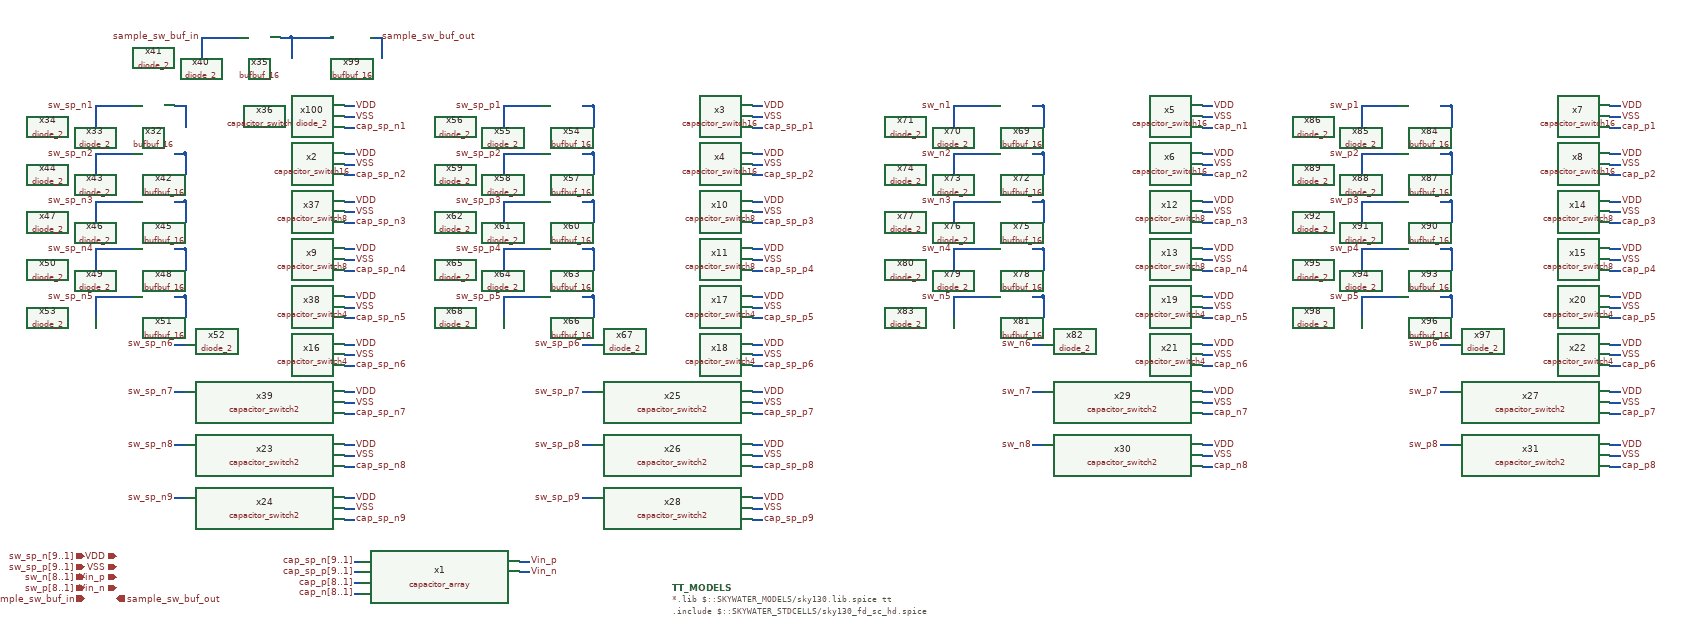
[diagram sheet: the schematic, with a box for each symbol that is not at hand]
v {xschem version=3.1.0 file_version=1.2
}
G {}
K {}
V {}
S {}
E {}
N 690 -110 700 -110 {
lab=cap_sp_n[9..1]}
N 690 -90 700 -90 {
lab=cap_sp_p[9..1]}
N 690 -70 700 -70 {
lab=cap_p[8..1]}
N 690 -50 700 -50 {
lab=cap_n[8..1]}
N 1000 -110 1020 -110 {
lab=Vin_p}
N 1000 -90 1020 -90 {
lab=Vin_n}
N 670 -930 690 -930 {
lab=cap_sp_n1}
N 670 -970 690 -970 {
lab=VDD}
N 670 -950 690 -950 {
lab=VSS}
N 350 -970 370 -970 {
lab=sw_sp_n1}
N 670 -840 690 -840 {
lab=cap_sp_n2}
N 670 -880 690 -880 {
lab=VDD}
N 670 -860 690 -860 {
lab=VSS}
N 350 -880 370 -880 {
lab=sw_sp_n2}
N 670 -750 690 -750 {
lab=cap_sp_n3}
N 670 -790 690 -790 {
lab=VDD}
N 670 -770 690 -770 {
lab=VSS}
N 350 -790 370 -790 {
lab=sw_sp_n3}
N 670 -660 690 -660 {
lab=cap_sp_n4}
N 670 -700 690 -700 {
lab=VDD}
N 670 -680 690 -680 {
lab=VSS}
N 350 -700 370 -700 {
lab=sw_sp_n4}
N 670 -570 690 -570 {
lab=cap_sp_n5}
N 670 -610 690 -610 {
lab=VDD}
N 670 -590 690 -590 {
lab=VSS}
N 350 -610 370 -610 {
lab=sw_sp_n5}
N 670 -480 690 -480 {
lab=cap_sp_n6}
N 670 -520 690 -520 {
lab=VDD}
N 670 -500 690 -500 {
lab=VSS}
N 350 -520 370 -520 {
lab=sw_sp_n6}
N 670 -390 690 -390 {
lab=cap_sp_n7}
N 670 -430 690 -430 {
lab=VDD}
N 670 -410 690 -410 {
lab=VSS}
N 350 -430 370 -430 {
lab=sw_sp_n7}
N 670 -290 690 -290 {
lab=cap_sp_n8}
N 670 -330 690 -330 {
lab=VDD}
N 670 -310 690 -310 {
lab=VSS}
N 350 -330 370 -330 {
lab=sw_sp_n8}
N 670 -190 690 -190 {
lab=cap_sp_n9}
N 670 -230 690 -230 {
lab=VDD}
N 670 -210 690 -210 {
lab=VSS}
N 350 -230 370 -230 {
lab=sw_sp_n9}
N 1440 -930 1460 -930 {
lab=cap_sp_p1}
N 1440 -970 1460 -970 {
lab=VDD}
N 1440 -950 1460 -950 {
lab=VSS}
N 1120 -970 1140 -970 {
lab=sw_sp_p1}
N 1440 -840 1460 -840 {
lab=cap_sp_p2}
N 1440 -880 1460 -880 {
lab=VDD}
N 1440 -860 1460 -860 {
lab=VSS}
N 1120 -880 1140 -880 {
lab=sw_sp_p2}
N 1440 -750 1460 -750 {
lab=cap_sp_p3}
N 1440 -790 1460 -790 {
lab=VDD}
N 1440 -770 1460 -770 {
lab=VSS}
N 1120 -790 1140 -790 {
lab=sw_sp_p3}
N 1440 -660 1460 -660 {
lab=cap_sp_p4}
N 1440 -700 1460 -700 {
lab=VDD}
N 1440 -680 1460 -680 {
lab=VSS}
N 1120 -700 1140 -700 {
lab=sw_sp_p4}
N 1440 -570 1460 -570 {
lab=cap_sp_p5}
N 1440 -610 1460 -610 {
lab=VDD}
N 1440 -590 1460 -590 {
lab=VSS}
N 1120 -610 1140 -610 {
lab=sw_sp_p5}
N 1440 -480 1460 -480 {
lab=cap_sp_p6}
N 1440 -520 1460 -520 {
lab=VDD}
N 1440 -500 1460 -500 {
lab=VSS}
N 1120 -520 1140 -520 {
lab=sw_sp_p6}
N 1440 -390 1460 -390 {
lab=cap_sp_p7}
N 1440 -430 1460 -430 {
lab=VDD}
N 1440 -410 1460 -410 {
lab=VSS}
N 1120 -430 1140 -430 {
lab=sw_sp_p7}
N 1440 -290 1460 -290 {
lab=cap_sp_p8}
N 1440 -330 1460 -330 {
lab=VDD}
N 1440 -310 1460 -310 {
lab=VSS}
N 1120 -330 1140 -330 {
lab=sw_sp_p8}
N 1440 -190 1460 -190 {
lab=cap_sp_p9}
N 1440 -230 1460 -230 {
lab=VDD}
N 1440 -210 1460 -210 {
lab=VSS}
N 1120 -230 1140 -230 {
lab=sw_sp_p9}
N 3060 -930 3080 -930 {
lab=cap_p1}
N 3060 -970 3080 -970 {
lab=VDD}
N 3060 -950 3080 -950 {
lab=VSS}
N 2740 -970 2760 -970 {
lab=sw_p1}
N 3060 -840 3080 -840 {
lab=cap_p2}
N 3060 -880 3080 -880 {
lab=VDD}
N 3060 -860 3080 -860 {
lab=VSS}
N 2740 -880 2760 -880 {
lab=sw_p2}
N 3060 -750 3080 -750 {
lab=cap_p3}
N 3060 -790 3080 -790 {
lab=VDD}
N 3060 -770 3080 -770 {
lab=VSS}
N 2740 -790 2760 -790 {
lab=sw_p3}
N 3060 -660 3080 -660 {
lab=cap_p4}
N 3060 -700 3080 -700 {
lab=VDD}
N 3060 -680 3080 -680 {
lab=VSS}
N 2740 -700 2760 -700 {
lab=sw_p4}
N 3060 -570 3080 -570 {
lab=cap_p5}
N 3060 -610 3080 -610 {
lab=VDD}
N 3060 -590 3080 -590 {
lab=VSS}
N 2740 -610 2760 -610 {
lab=sw_p5}
N 3060 -480 3080 -480 {
lab=cap_p6}
N 3060 -520 3080 -520 {
lab=VDD}
N 3060 -500 3080 -500 {
lab=VSS}
N 2740 -520 2760 -520 {
lab=sw_p6}
N 3060 -390 3080 -390 {
lab=cap_p7}
N 3060 -430 3080 -430 {
lab=VDD}
N 3060 -410 3080 -410 {
lab=VSS}
N 2740 -430 2760 -430 {
lab=sw_p7}
N 3060 -290 3080 -290 {
lab=cap_p8}
N 3060 -330 3080 -330 {
lab=VDD}
N 3060 -310 3080 -310 {
lab=VSS}
N 2740 -330 2760 -330 {
lab=sw_p8}
N 2290 -930 2310 -930 {
lab=cap_n1}
N 2290 -970 2310 -970 {
lab=VDD}
N 2290 -950 2310 -950 {
lab=VSS}
N 1970 -970 1990 -970 {
lab=sw_n1}
N 2290 -840 2310 -840 {
lab=cap_n2}
N 2290 -880 2310 -880 {
lab=VDD}
N 2290 -860 2310 -860 {
lab=VSS}
N 1970 -880 1990 -880 {
lab=sw_n2}
N 2290 -750 2310 -750 {
lab=cap_n3}
N 2290 -790 2310 -790 {
lab=VDD}
N 2290 -770 2310 -770 {
lab=VSS}
N 1970 -790 1990 -790 {
lab=sw_n3}
N 2290 -660 2310 -660 {
lab=cap_n4}
N 2290 -700 2310 -700 {
lab=VDD}
N 2290 -680 2310 -680 {
lab=VSS}
N 1970 -700 1990 -700 {
lab=sw_n4}
N 2290 -570 2310 -570 {
lab=cap_n5}
N 2290 -610 2310 -610 {
lab=VDD}
N 2290 -590 2310 -590 {
lab=VSS}
N 1970 -610 1990 -610 {
lab=sw_n5}
N 2290 -480 2310 -480 {
lab=cap_n6}
N 2290 -520 2310 -520 {
lab=VDD}
N 2290 -500 2310 -500 {
lab=VSS}
N 1970 -520 1990 -520 {
lab=sw_n6}
N 2290 -390 2310 -390 {
lab=cap_n7}
N 2290 -430 2310 -430 {
lab=VDD}
N 2290 -410 2310 -410 {
lab=VSS}
N 1970 -430 1990 -430 {
lab=sw_n7}
N 2290 -290 2310 -290 {
lab=cap_n8}
N 2290 -330 2310 -330 {
lab=VDD}
N 2290 -310 2310 -310 {
lab=VSS}
N 1970 -330 1990 -330 {
lab=sw_n8}
N 370 -970 370 -930 {}
N 210 -970 270 -970 {}
N 200 -970 200 -930 {}
N 200 -970 210 -970 {}
N 550 -1100 570 -1100 {
lab=sw_sp_n1}
N 570 -1100 570 -1060 {}
N 410 -1100 470 -1100 {}
N 400 -1100 400 -1060 {}
N 400 -1100 410 -1100 {}
N 350 -880 370 -880 {
lab=sw_sp_n1}
N 370 -880 370 -840 {}
N 210 -880 270 -880 {}
N 200 -880 200 -840 {}
N 200 -880 210 -880 {}
N 350 -790 370 -790 {
lab=sw_sp_n1}
N 370 -790 370 -750 {}
N 210 -790 270 -790 {}
N 200 -790 200 -750 {}
N 200 -790 210 -790 {}
N 350 -700 370 -700 {
lab=sw_sp_n1}
N 370 -700 370 -660 {}
N 210 -700 270 -700 {}
N 200 -700 200 -660 {}
N 200 -700 210 -700 {}
N 350 -610 370 -610 {
lab=sw_sp_n1}
N 370 -610 370 -570 {}
N 210 -610 270 -610 {}
N 200 -610 200 -570 {}
N 200 -610 210 -610 {}
N 1120 -970 1140 -970 {
lab=sw_sp_n1}
N 1140 -970 1140 -930 {}
N 980 -970 1040 -970 {}
N 970 -970 970 -930 {}
N 970 -970 980 -970 {}
N 1120 -880 1140 -880 {
lab=sw_sp_n1}
N 1140 -880 1140 -840 {}
N 980 -880 1040 -880 {}
N 970 -880 970 -840 {}
N 970 -880 980 -880 {}
N 1120 -790 1140 -790 {
lab=sw_sp_n1}
N 1140 -790 1140 -750 {}
N 980 -790 1040 -790 {}
N 970 -790 970 -750 {}
N 970 -790 980 -790 {}
N 1120 -700 1140 -700 {
lab=sw_sp_n1}
N 1140 -700 1140 -660 {}
N 980 -700 1040 -700 {}
N 970 -700 970 -660 {}
N 970 -700 980 -700 {}
N 1120 -610 1140 -610 {
lab=sw_sp_n1}
N 1140 -610 1140 -570 {}
N 980 -610 1040 -610 {}
N 970 -610 970 -570 {}
N 970 -610 980 -610 {}
N 1970 -970 1990 -970 {
lab=sw_sp_n1}
N 1990 -970 1990 -930 {}
N 1830 -970 1890 -970 {}
N 1820 -970 1820 -930 {}
N 1820 -970 1830 -970 {}
N 1970 -880 1990 -880 {
lab=sw_sp_n1}
N 1990 -880 1990 -840 {}
N 1830 -880 1890 -880 {}
N 1820 -880 1820 -840 {}
N 1820 -880 1830 -880 {}
N 1970 -790 1990 -790 {
lab=sw_sp_n1}
N 1990 -790 1990 -750 {}
N 1830 -790 1890 -790 {}
N 1820 -790 1820 -750 {}
N 1820 -790 1830 -790 {}
N 1970 -700 1990 -700 {
lab=sw_sp_n1}
N 1990 -700 1990 -660 {}
N 1830 -700 1890 -700 {}
N 1820 -700 1820 -660 {}
N 1820 -700 1830 -700 {}
N 1970 -610 1990 -610 {
lab=sw_sp_n1}
N 1990 -610 1990 -570 {}
N 1830 -610 1890 -610 {}
N 1820 -610 1820 -570 {}
N 1820 -610 1830 -610 {}
N 2740 -970 2760 -970 {
lab=sw_sp_n1}
N 2760 -970 2760 -930 {}
N 2600 -970 2660 -970 {}
N 2590 -970 2590 -930 {}
N 2590 -970 2600 -970 {}
N 2740 -880 2760 -880 {
lab=sw_sp_n1}
N 2760 -880 2760 -840 {}
N 2600 -880 2660 -880 {}
N 2590 -880 2590 -840 {}
N 2590 -880 2600 -880 {}
N 2740 -790 2760 -790 {
lab=sw_sp_n1}
N 2760 -790 2760 -750 {}
N 2600 -790 2660 -790 {}
N 2590 -790 2590 -750 {}
N 2590 -790 2600 -790 {}
N 2740 -700 2760 -700 {
lab=sw_sp_n1}
N 2760 -700 2760 -660 {}
N 2600 -700 2660 -700 {}
N 2590 -700 2590 -660 {}
N 2590 -700 2600 -700 {}
N 2740 -610 2760 -610 {
lab=sw_sp_n1}
N 2760 -610 2760 -570 {}
N 2600 -610 2660 -610 {}
N 2590 -610 2590 -570 {}
N 2590 -610 2600 -610 {}
N 720 -1100 740 -1100 {
lab=sw_sp_n1}
N 740 -1100 740 -1060 {}
N 580 -1100 640 -1100 {}
N 570 -1100 580 -1100 {}
N 640 -1100 650 -1100 {}
C {devices/title.sym} 160 30 0 0 {name=l1 author="Dr. Aubrey Beal, Dr. Phillip Bailey, Micah Tseng"
}
C {src/capacitor_array/capacitor_array.sym} 850 -80 0 0 {name=x1 unit_cap_w=5 unit_cap_l=5
}
C {devices/iopin.sym} 240 -120 0 0 {name=p1 lab=VDD
}
C {devices/ipin.sym} 180 -120 0 0 {name=p3 lab=sw_sp_n[9..1]
}
C {devices/iopin.sym} 240 -100 0 0 {name=p4 lab=VSS
}
C {devices/iopin.sym} 240 -80 0 0 {name=p5 lab=Vin_p
}
C {devices/iopin.sym} 240 -60 0 0 {name=p6 lab=Vin_n
}
C {devices/ipin.sym} 180 -100 0 0 {name=p2 lab=sw_sp_p[9..1]
}
C {devices/ipin.sym} 180 -80 0 0 {name=p7 lab=sw_n[8..1]
}
C {devices/ipin.sym} 180 -60 0 0 {name=p8 lab=sw_p[8..1]
}
C {devices/lab_pin.sym} 690 -110 0 0 {name=l2 sig_type=std_logic lab=cap_sp_n[9..1]
}
C {devices/lab_pin.sym} 690 -90 0 0 {name=l3 sig_type=std_logic lab=cap_sp_p[9..1]
}
C {devices/lab_pin.sym} 690 -70 0 0 {name=l4 sig_type=std_logic lab=cap_p[8..1]
}
C {devices/lab_pin.sym} 690 -50 0 0 {name=l5 sig_type=std_logic lab=cap_n[8..1]
}
C {devices/lab_pin.sym} 1020 -110 2 0 {name=l6 sig_type=std_logic lab=Vin_p
}
C {devices/lab_pin.sym} 1020 -90 2 0 {name=l7 sig_type=std_logic lab=Vin_n
}
C {devices/lab_pin.sym} 690 -930 2 0 {name=l8 sig_type=std_logic lab=cap_sp_n1
}
C {devices/lab_pin.sym} 690 -970 2 0 {name=l9 sig_type=std_logic lab=VDD
}
C {devices/lab_pin.sym} 690 -950 2 0 {name=l10 sig_type=std_logic lab=VSS
}
C {devices/lab_pin.sym} 200 -970 0 0 {name=l11 sig_type=std_logic lab=sw_sp_n1
}
C {devices/lab_pin.sym} 690 -840 2 0 {name=l12 sig_type=std_logic lab=cap_sp_n2
}
C {devices/lab_pin.sym} 690 -880 2 0 {name=l13 sig_type=std_logic lab=VDD
}
C {devices/lab_pin.sym} 690 -860 2 0 {name=l14 sig_type=std_logic lab=VSS
}
C {devices/lab_pin.sym} 200 -880 0 0 {name=l15 sig_type=std_logic lab=sw_sp_n2
}
C {devices/lab_pin.sym} 690 -750 2 0 {name=l16 sig_type=std_logic lab=cap_sp_n3
}
C {devices/lab_pin.sym} 690 -790 2 0 {name=l17 sig_type=std_logic lab=VDD
}
C {devices/lab_pin.sym} 690 -770 2 0 {name=l18 sig_type=std_logic lab=VSS
}
C {devices/lab_pin.sym} 200 -790 0 0 {name=l19 sig_type=std_logic lab=sw_sp_n3
}
C {devices/lab_pin.sym} 690 -660 2 0 {name=l20 sig_type=std_logic lab=cap_sp_n4
}
C {devices/lab_pin.sym} 690 -700 2 0 {name=l21 sig_type=std_logic lab=VDD
}
C {devices/lab_pin.sym} 690 -680 2 0 {name=l22 sig_type=std_logic lab=VSS
}
C {devices/lab_pin.sym} 690 -570 2 0 {name=l24 sig_type=std_logic lab=cap_sp_n5
}
C {devices/lab_pin.sym} 690 -610 2 0 {name=l25 sig_type=std_logic lab=VDD
}
C {devices/lab_pin.sym} 690 -590 2 0 {name=l26 sig_type=std_logic lab=VSS
}
C {devices/lab_pin.sym} 200 -610 0 0 {name=l27 sig_type=std_logic lab=sw_sp_n5
}
C {devices/lab_pin.sym} 690 -480 2 0 {name=l28 sig_type=std_logic lab=cap_sp_n6
}
C {devices/lab_pin.sym} 690 -520 2 0 {name=l29 sig_type=std_logic lab=VDD
}
C {devices/lab_pin.sym} 690 -500 2 0 {name=l30 sig_type=std_logic lab=VSS
}
C {devices/lab_pin.sym} 350 -520 0 0 {name=l31 sig_type=std_logic lab=sw_sp_n6
}
C {devices/lab_pin.sym} 690 -390 2 0 {name=l32 sig_type=std_logic lab=cap_sp_n7
}
C {devices/lab_pin.sym} 690 -430 2 0 {name=l33 sig_type=std_logic lab=VDD
}
C {devices/lab_pin.sym} 690 -410 2 0 {name=l34 sig_type=std_logic lab=VSS
}
C {devices/lab_pin.sym} 350 -430 0 0 {name=l35 sig_type=std_logic lab=sw_sp_n7
}
C {devices/lab_pin.sym} 690 -290 2 0 {name=l36 sig_type=std_logic lab=cap_sp_n8
}
C {devices/lab_pin.sym} 690 -330 2 0 {name=l37 sig_type=std_logic lab=VDD
}
C {devices/lab_pin.sym} 690 -310 2 0 {name=l38 sig_type=std_logic lab=VSS
}
C {devices/lab_pin.sym} 350 -330 0 0 {name=l39 sig_type=std_logic lab=sw_sp_n8
}
C {devices/lab_pin.sym} 690 -190 2 0 {name=l40 sig_type=std_logic lab=cap_sp_n9
}
C {devices/lab_pin.sym} 690 -230 2 0 {name=l41 sig_type=std_logic lab=VDD
}
C {devices/lab_pin.sym} 690 -210 2 0 {name=l42 sig_type=std_logic lab=VSS
}
C {devices/lab_pin.sym} 350 -230 0 0 {name=l43 sig_type=std_logic lab=sw_sp_n9
}
C {devices/lab_pin.sym} 1460 -930 2 0 {name=l44 sig_type=std_logic lab=cap_sp_p1
}
C {devices/lab_pin.sym} 1460 -970 2 0 {name=l45 sig_type=std_logic lab=VDD
}
C {devices/lab_pin.sym} 1460 -950 2 0 {name=l46 sig_type=std_logic lab=VSS
}
C {devices/lab_pin.sym} 970 -970 0 0 {name=l47 sig_type=std_logic lab=sw_sp_p1
}
C {devices/lab_pin.sym} 1460 -840 2 0 {name=l48 sig_type=std_logic lab=cap_sp_p2
}
C {devices/lab_pin.sym} 1460 -880 2 0 {name=l49 sig_type=std_logic lab=VDD
}
C {devices/lab_pin.sym} 1460 -860 2 0 {name=l50 sig_type=std_logic lab=VSS
}
C {devices/lab_pin.sym} 970 -880 0 0 {name=l51 sig_type=std_logic lab=sw_sp_p2
}
C {devices/lab_pin.sym} 1460 -750 2 0 {name=l52 sig_type=std_logic lab=cap_sp_p3
}
C {devices/lab_pin.sym} 1460 -790 2 0 {name=l53 sig_type=std_logic lab=VDD
}
C {devices/lab_pin.sym} 1460 -770 2 0 {name=l54 sig_type=std_logic lab=VSS
}
C {devices/lab_pin.sym} 970 -790 0 0 {name=l55 sig_type=std_logic lab=sw_sp_p3
}
C {devices/lab_pin.sym} 1460 -660 2 0 {name=l56 sig_type=std_logic lab=cap_sp_p4
}
C {devices/lab_pin.sym} 1460 -700 2 0 {name=l57 sig_type=std_logic lab=VDD
}
C {devices/lab_pin.sym} 1460 -680 2 0 {name=l58 sig_type=std_logic lab=VSS
}
C {devices/lab_pin.sym} 970 -700 0 0 {name=l59 sig_type=std_logic lab=sw_sp_p4
}
C {devices/lab_pin.sym} 1460 -570 2 0 {name=l60 sig_type=std_logic lab=cap_sp_p5
}
C {devices/lab_pin.sym} 1460 -610 2 0 {name=l61 sig_type=std_logic lab=VDD
}
C {devices/lab_pin.sym} 1460 -590 2 0 {name=l62 sig_type=std_logic lab=VSS
}
C {devices/lab_pin.sym} 970 -610 0 0 {name=l63 sig_type=std_logic lab=sw_sp_p5
}
C {devices/lab_pin.sym} 1460 -480 2 0 {name=l64 sig_type=std_logic lab=cap_sp_p6
}
C {devices/lab_pin.sym} 1460 -520 2 0 {name=l65 sig_type=std_logic lab=VDD
}
C {devices/lab_pin.sym} 1460 -500 2 0 {name=l66 sig_type=std_logic lab=VSS
}
C {devices/lab_pin.sym} 1120 -520 0 0 {name=l67 sig_type=std_logic lab=sw_sp_p6
}
C {devices/lab_pin.sym} 1460 -390 2 0 {name=l68 sig_type=std_logic lab=cap_sp_p7
}
C {devices/lab_pin.sym} 1460 -430 2 0 {name=l69 sig_type=std_logic lab=VDD
}
C {devices/lab_pin.sym} 1460 -410 2 0 {name=l70 sig_type=std_logic lab=VSS
}
C {devices/lab_pin.sym} 1120 -430 0 0 {name=l71 sig_type=std_logic lab=sw_sp_p7
}
C {devices/lab_pin.sym} 1460 -290 2 0 {name=l72 sig_type=std_logic lab=cap_sp_p8
}
C {devices/lab_pin.sym} 1460 -330 2 0 {name=l73 sig_type=std_logic lab=VDD
}
C {devices/lab_pin.sym} 1460 -310 2 0 {name=l74 sig_type=std_logic lab=VSS
}
C {devices/lab_pin.sym} 1120 -330 0 0 {name=l75 sig_type=std_logic lab=sw_sp_p8
}
C {devices/lab_pin.sym} 1460 -190 2 0 {name=l76 sig_type=std_logic lab=cap_sp_p9
}
C {devices/lab_pin.sym} 1460 -230 2 0 {name=l77 sig_type=std_logic lab=VDD
}
C {devices/lab_pin.sym} 1460 -210 2 0 {name=l78 sig_type=std_logic lab=VSS
}
C {devices/lab_pin.sym} 1120 -230 0 0 {name=l79 sig_type=std_logic lab=sw_sp_p9
}
C {devices/lab_pin.sym} 3080 -930 2 0 {name=l80 sig_type=std_logic lab=cap_p1
}
C {devices/lab_pin.sym} 3080 -970 2 0 {name=l81 sig_type=std_logic lab=VDD
}
C {devices/lab_pin.sym} 3080 -950 2 0 {name=l82 sig_type=std_logic lab=VSS
}
C {devices/lab_pin.sym} 2590 -970 0 0 {name=l83 sig_type=std_logic lab=sw_p1
}
C {devices/lab_pin.sym} 3080 -840 2 0 {name=l84 sig_type=std_logic lab=cap_p2
}
C {devices/lab_pin.sym} 3080 -880 2 0 {name=l85 sig_type=std_logic lab=VDD
}
C {devices/lab_pin.sym} 3080 -860 2 0 {name=l86 sig_type=std_logic lab=VSS
}
C {devices/lab_pin.sym} 2590 -880 0 0 {name=l87 sig_type=std_logic lab=sw_p2
}
C {devices/lab_pin.sym} 3080 -750 2 0 {name=l88 sig_type=std_logic lab=cap_p3
}
C {devices/lab_pin.sym} 3080 -790 2 0 {name=l89 sig_type=std_logic lab=VDD
}
C {devices/lab_pin.sym} 3080 -770 2 0 {name=l90 sig_type=std_logic lab=VSS
}
C {devices/lab_pin.sym} 2590 -790 0 0 {name=l91 sig_type=std_logic lab=sw_p3
}
C {devices/lab_pin.sym} 3080 -660 2 0 {name=l92 sig_type=std_logic lab=cap_p4
}
C {devices/lab_pin.sym} 3080 -700 2 0 {name=l93 sig_type=std_logic lab=VDD
}
C {devices/lab_pin.sym} 3080 -680 2 0 {name=l94 sig_type=std_logic lab=VSS
}
C {devices/lab_pin.sym} 2590 -700 0 0 {name=l95 sig_type=std_logic lab=sw_p4
}
C {devices/lab_pin.sym} 3080 -570 2 0 {name=l96 sig_type=std_logic lab=cap_p5
}
C {devices/lab_pin.sym} 3080 -610 2 0 {name=l97 sig_type=std_logic lab=VDD
}
C {devices/lab_pin.sym} 3080 -590 2 0 {name=l98 sig_type=std_logic lab=VSS
}
C {devices/lab_pin.sym} 2590 -610 0 0 {name=l99 sig_type=std_logic lab=sw_p5
}
C {devices/lab_pin.sym} 3080 -480 2 0 {name=l100 sig_type=std_logic lab=cap_p6
}
C {devices/lab_pin.sym} 3080 -520 2 0 {name=l101 sig_type=std_logic lab=VDD
}
C {devices/lab_pin.sym} 3080 -500 2 0 {name=l102 sig_type=std_logic lab=VSS
}
C {devices/lab_pin.sym} 2740 -520 0 0 {name=l103 sig_type=std_logic lab=sw_p6
}
C {devices/lab_pin.sym} 3080 -390 2 0 {name=l104 sig_type=std_logic lab=cap_p7
}
C {devices/lab_pin.sym} 3080 -430 2 0 {name=l105 sig_type=std_logic lab=VDD
}
C {devices/lab_pin.sym} 3080 -410 2 0 {name=l106 sig_type=std_logic lab=VSS
}
C {devices/lab_pin.sym} 2740 -430 0 0 {name=l107 sig_type=std_logic lab=sw_p7
}
C {devices/lab_pin.sym} 3080 -290 2 0 {name=l108 sig_type=std_logic lab=cap_p8
}
C {devices/lab_pin.sym} 3080 -330 2 0 {name=l109 sig_type=std_logic lab=VDD
}
C {devices/lab_pin.sym} 3080 -310 2 0 {name=l110 sig_type=std_logic lab=VSS
}
C {devices/lab_pin.sym} 2740 -330 0 0 {name=l111 sig_type=std_logic lab=sw_p8
}
C {devices/lab_pin.sym} 2310 -930 2 0 {name=l112 sig_type=std_logic lab=cap_n1
}
C {devices/lab_pin.sym} 2310 -970 2 0 {name=l113 sig_type=std_logic lab=VDD
}
C {devices/lab_pin.sym} 2310 -950 2 0 {name=l114 sig_type=std_logic lab=VSS
}
C {devices/lab_pin.sym} 1820 -970 0 0 {name=l115 sig_type=std_logic lab=sw_n1
}
C {devices/lab_pin.sym} 2310 -840 2 0 {name=l116 sig_type=std_logic lab=cap_n2
}
C {devices/lab_pin.sym} 2310 -880 2 0 {name=l117 sig_type=std_logic lab=VDD
}
C {devices/lab_pin.sym} 2310 -860 2 0 {name=l118 sig_type=std_logic lab=VSS
}
C {devices/lab_pin.sym} 1820 -880 0 0 {name=l119 sig_type=std_logic lab=sw_n2
}
C {devices/lab_pin.sym} 2310 -750 2 0 {name=l120 sig_type=std_logic lab=cap_n3
}
C {devices/lab_pin.sym} 2310 -790 2 0 {name=l121 sig_type=std_logic lab=VDD
}
C {devices/lab_pin.sym} 2310 -770 2 0 {name=l122 sig_type=std_logic lab=VSS
}
C {devices/lab_pin.sym} 1820 -790 0 0 {name=l123 sig_type=std_logic lab=sw_n3
}
C {devices/lab_pin.sym} 2310 -660 2 0 {name=l124 sig_type=std_logic lab=cap_n4
}
C {devices/lab_pin.sym} 2310 -700 2 0 {name=l125 sig_type=std_logic lab=VDD
}
C {devices/lab_pin.sym} 2310 -680 2 0 {name=l126 sig_type=std_logic lab=VSS
}
C {devices/lab_pin.sym} 1820 -700 0 0 {name=l127 sig_type=std_logic lab=sw_n4
}
C {devices/lab_pin.sym} 2310 -570 2 0 {name=l128 sig_type=std_logic lab=cap_n5
}
C {devices/lab_pin.sym} 2310 -610 2 0 {name=l129 sig_type=std_logic lab=VDD
}
C {devices/lab_pin.sym} 2310 -590 2 0 {name=l130 sig_type=std_logic lab=VSS
}
C {devices/lab_pin.sym} 1820 -610 0 0 {name=l131 sig_type=std_logic lab=sw_n5
}
C {devices/lab_pin.sym} 2310 -480 2 0 {name=l132 sig_type=std_logic lab=cap_n6
}
C {devices/lab_pin.sym} 2310 -520 2 0 {name=l133 sig_type=std_logic lab=VDD
}
C {devices/lab_pin.sym} 2310 -500 2 0 {name=l134 sig_type=std_logic lab=VSS
}
C {devices/lab_pin.sym} 1970 -520 0 0 {name=l135 sig_type=std_logic lab=sw_n6
}
C {devices/lab_pin.sym} 2310 -390 2 0 {name=l136 sig_type=std_logic lab=cap_n7
}
C {devices/lab_pin.sym} 2310 -430 2 0 {name=l137 sig_type=std_logic lab=VDD
}
C {devices/lab_pin.sym} 2310 -410 2 0 {name=l138 sig_type=std_logic lab=VSS
}
C {devices/lab_pin.sym} 1970 -430 0 0 {name=l139 sig_type=std_logic lab=sw_n7
}
C {devices/lab_pin.sym} 2310 -290 2 0 {name=l140 sig_type=std_logic lab=cap_n8
}
C {devices/lab_pin.sym} 2310 -330 2 0 {name=l141 sig_type=std_logic lab=VDD
}
C {devices/lab_pin.sym} 2310 -310 2 0 {name=l142 sig_type=std_logic lab=VSS
}
C {devices/lab_pin.sym} 1970 -330 0 0 {name=l143 sig_type=std_logic lab=sw_n8
}
C {src/capacitor_switch16/capacitor_switch16.sym} 520 -950 0 0 {name=x36}
C {src/capacitor_switch8/capacitor_switch8.sym} 520 -770 0 0 {name=x37}
C {src/capacitor_switch4/capacitor_switch4.sym} 520 -590 0 0 {name=x38}
C {src/capacitor_switch2/capacitor_switch2.sym} 520 -410 0 0 {name=x39}
C {src/capacitor_switch16/capacitor_switch16.sym} 520 -860 0 0 {name=x2}
C {src/capacitor_switch16/capacitor_switch16.sym} 1290 -950 0 0 {name=x3}
C {src/capacitor_switch16/capacitor_switch16.sym} 1290 -860 0 0 {name=x4}
C {src/capacitor_switch16/capacitor_switch16.sym} 2140 -950 0 0 {name=x5}
C {src/capacitor_switch16/capacitor_switch16.sym} 2140 -860 0 0 {name=x6}
C {src/capacitor_switch16/capacitor_switch16.sym} 2910 -950 0 0 {name=x7}
C {src/capacitor_switch16/capacitor_switch16.sym} 2910 -860 0 0 {name=x8}
C {src/capacitor_switch8/capacitor_switch8.sym} 520 -680 0 0 {name=x9}
C {src/capacitor_switch8/capacitor_switch8.sym} 1290 -770 0 0 {name=x10}
C {src/capacitor_switch8/capacitor_switch8.sym} 1290 -680 0 0 {name=x11}
C {src/capacitor_switch8/capacitor_switch8.sym} 2140 -770 0 0 {name=x12}
C {src/capacitor_switch8/capacitor_switch8.sym} 2140 -680 0 0 {name=x13}
C {src/capacitor_switch8/capacitor_switch8.sym} 2910 -770 0 0 {name=x14}
C {src/capacitor_switch8/capacitor_switch8.sym} 2910 -680 0 0 {name=x15}
C {src/capacitor_switch4/capacitor_switch4.sym} 520 -500 0 0 {name=x16}
C {src/capacitor_switch4/capacitor_switch4.sym} 1290 -590 0 0 {name=x17}
C {src/capacitor_switch4/capacitor_switch4.sym} 1290 -500 0 0 {name=x18}
C {src/capacitor_switch4/capacitor_switch4.sym} 2140 -590 0 0 {name=x19}
C {src/capacitor_switch4/capacitor_switch4.sym} 2910 -590 0 0 {name=x20}
C {src/capacitor_switch4/capacitor_switch4.sym} 2140 -500 0 0 {name=x21}
C {src/capacitor_switch4/capacitor_switch4.sym} 2910 -500 0 0 {name=x22}
C {src/capacitor_switch2/capacitor_switch2.sym} 520 -310 0 0 {name=x23}
C {src/capacitor_switch2/capacitor_switch2.sym} 520 -210 0 0 {name=x24}
C {src/capacitor_switch2/capacitor_switch2.sym} 1290 -410 0 0 {name=x25}
C {src/capacitor_switch2/capacitor_switch2.sym} 1290 -310 0 0 {name=x26}
C {src/capacitor_switch2/capacitor_switch2.sym} 1290 -210 0 0 {name=x28}
C {src/capacitor_switch2/capacitor_switch2.sym} 2140 -410 0 0 {name=x29}
C {src/capacitor_switch2/capacitor_switch2.sym} 2140 -310 0 0 {name=x30}
C {src/capacitor_switch2/capacitor_switch2.sym} 2910 -410 0 0 {name=x27}
C {src/capacitor_switch2/capacitor_switch2.sym} 2910 -310 0 0 {name=x31}
C {sky130_stdcells/bufbuf_16.sym} 310 -970 0 0 {name=x32 VGND=VSS VNB=VSS VPB=VDD VPWR=VDD prefix=sky130_fd_sc_hd__ 
}
C {sky130_stdcells/diode_2.sym} 280 -930 2 0 {name=x33 VGND=VSS VNB=VSS VPB=VDD VPWR=VDD prefix=sky130_fd_sc_hd__ 
}
C {sky130_stdcells/diode_2.sym} 110 -930 2 0 {name=x34 VGND=VSS VNB=VSS VPB=VDD VPWR=VDD prefix=sky130_fd_sc_hd__ 
}
C {sky130_stdcells/bufbuf_16.sym} 510 -1100 0 0 {name=x35 VGND=VSS VNB=VSS VPB=VDD VPWR=VDD prefix=sky130_fd_sc_hd__ 
}
C {sky130_stdcells/diode_2.sym} 480 -1060 2 0 {name=x40 VGND=VSS VNB=VSS VPB=VDD VPWR=VDD prefix=sky130_fd_sc_hd__ 
}
C {sky130_stdcells/diode_2.sym} 310 -1060 2 0 {name=x41 VGND=VSS VNB=VSS VPB=VDD VPWR=VDD prefix=sky130_fd_sc_hd__ 
}
C {sky130_stdcells/bufbuf_16.sym} 310 -880 0 0 {name=x42 VGND=VSS VNB=VSS VPB=VDD VPWR=VDD prefix=sky130_fd_sc_hd__ 
}
C {sky130_stdcells/diode_2.sym} 280 -840 2 0 {name=x43 VGND=VSS VNB=VSS VPB=VDD VPWR=VDD prefix=sky130_fd_sc_hd__ 
}
C {sky130_stdcells/diode_2.sym} 110 -840 2 0 {name=x44 VGND=VSS VNB=VSS VPB=VDD VPWR=VDD prefix=sky130_fd_sc_hd__ 
}
C {sky130_stdcells/bufbuf_16.sym} 310 -790 0 0 {name=x45 VGND=VSS VNB=VSS VPB=VDD VPWR=VDD prefix=sky130_fd_sc_hd__ 
}
C {sky130_stdcells/diode_2.sym} 280 -750 2 0 {name=x46 VGND=VSS VNB=VSS VPB=VDD VPWR=VDD prefix=sky130_fd_sc_hd__ 
}
C {sky130_stdcells/diode_2.sym} 110 -750 2 0 {name=x47 VGND=VSS VNB=VSS VPB=VDD VPWR=VDD prefix=sky130_fd_sc_hd__ 
}
C {devices/lab_pin.sym} 200 -700 0 0 {name=l23 sig_type=std_logic lab=sw_sp_n4
}
C {sky130_stdcells/bufbuf_16.sym} 310 -700 0 0 {name=x48 VGND=VSS VNB=VSS VPB=VDD VPWR=VDD prefix=sky130_fd_sc_hd__ 
}
C {sky130_stdcells/diode_2.sym} 280 -660 2 0 {name=x49 VGND=VSS VNB=VSS VPB=VDD VPWR=VDD prefix=sky130_fd_sc_hd__ 
}
C {sky130_stdcells/diode_2.sym} 110 -660 2 0 {name=x50 VGND=VSS VNB=VSS VPB=VDD VPWR=VDD prefix=sky130_fd_sc_hd__ 
}
C {sky130_stdcells/bufbuf_16.sym} 310 -610 0 0 {name=x51 VGND=VSS VNB=VSS VPB=VDD VPWR=VDD prefix=sky130_fd_sc_hd__ 
}
C {sky130_stdcells/diode_2.sym} 280 -570 2 0 {name=x52 VGND=VSS VNB=VSS VPB=VDD VPWR=VDD prefix=sky130_fd_sc_hd__ 
}
C {sky130_stdcells/diode_2.sym} 110 -570 2 0 {name=x53 VGND=VSS VNB=VSS VPB=VDD VPWR=VDD prefix=sky130_fd_sc_hd__ 
}
C {sky130_stdcells/bufbuf_16.sym} 1080 -970 0 0 {name=x54 VGND=VSS VNB=VSS VPB=VDD VPWR=VDD prefix=sky130_fd_sc_hd__ 
}
C {sky130_stdcells/diode_2.sym} 1050 -930 2 0 {name=x55 VGND=VSS VNB=VSS VPB=VDD VPWR=VDD prefix=sky130_fd_sc_hd__ 
}
C {sky130_stdcells/diode_2.sym} 880 -930 2 0 {name=x56 VGND=VSS VNB=VSS VPB=VDD VPWR=VDD prefix=sky130_fd_sc_hd__ 
}
C {sky130_stdcells/bufbuf_16.sym} 1080 -880 0 0 {name=x57 VGND=VSS VNB=VSS VPB=VDD VPWR=VDD prefix=sky130_fd_sc_hd__ 
}
C {sky130_stdcells/diode_2.sym} 1050 -840 2 0 {name=x58 VGND=VSS VNB=VSS VPB=VDD VPWR=VDD prefix=sky130_fd_sc_hd__ 
}
C {sky130_stdcells/diode_2.sym} 880 -840 2 0 {name=x59 VGND=VSS VNB=VSS VPB=VDD VPWR=VDD prefix=sky130_fd_sc_hd__ 
}
C {sky130_stdcells/bufbuf_16.sym} 1080 -790 0 0 {name=x60 VGND=VSS VNB=VSS VPB=VDD VPWR=VDD prefix=sky130_fd_sc_hd__ 
}
C {sky130_stdcells/diode_2.sym} 1050 -750 2 0 {name=x61 VGND=VSS VNB=VSS VPB=VDD VPWR=VDD prefix=sky130_fd_sc_hd__ 
}
C {sky130_stdcells/diode_2.sym} 880 -750 2 0 {name=x62 VGND=VSS VNB=VSS VPB=VDD VPWR=VDD prefix=sky130_fd_sc_hd__ 
}
C {sky130_stdcells/bufbuf_16.sym} 1080 -700 0 0 {name=x63 VGND=VSS VNB=VSS VPB=VDD VPWR=VDD prefix=sky130_fd_sc_hd__ 
}
C {sky130_stdcells/diode_2.sym} 1050 -660 2 0 {name=x64 VGND=VSS VNB=VSS VPB=VDD VPWR=VDD prefix=sky130_fd_sc_hd__ 
}
C {sky130_stdcells/diode_2.sym} 880 -660 2 0 {name=x65 VGND=VSS VNB=VSS VPB=VDD VPWR=VDD prefix=sky130_fd_sc_hd__ 
}
C {sky130_stdcells/bufbuf_16.sym} 1080 -610 0 0 {name=x66 VGND=VSS VNB=VSS VPB=VDD VPWR=VDD prefix=sky130_fd_sc_hd__ 
}
C {sky130_stdcells/diode_2.sym} 1050 -570 2 0 {name=x67 VGND=VSS VNB=VSS VPB=VDD VPWR=VDD prefix=sky130_fd_sc_hd__ 
}
C {sky130_stdcells/diode_2.sym} 880 -570 2 0 {name=x68 VGND=VSS VNB=VSS VPB=VDD VPWR=VDD prefix=sky130_fd_sc_hd__ 
}
C {sky130_stdcells/bufbuf_16.sym} 1930 -970 0 0 {name=x69 VGND=VSS VNB=VSS VPB=VDD VPWR=VDD prefix=sky130_fd_sc_hd__ 
}
C {sky130_stdcells/diode_2.sym} 1900 -930 2 0 {name=x70 VGND=VSS VNB=VSS VPB=VDD VPWR=VDD prefix=sky130_fd_sc_hd__ 
}
C {sky130_stdcells/diode_2.sym} 1730 -930 2 0 {name=x71 VGND=VSS VNB=VSS VPB=VDD VPWR=VDD prefix=sky130_fd_sc_hd__ 
}
C {sky130_stdcells/bufbuf_16.sym} 1930 -880 0 0 {name=x72 VGND=VSS VNB=VSS VPB=VDD VPWR=VDD prefix=sky130_fd_sc_hd__ 
}
C {sky130_stdcells/diode_2.sym} 1900 -840 2 0 {name=x73 VGND=VSS VNB=VSS VPB=VDD VPWR=VDD prefix=sky130_fd_sc_hd__ 
}
C {sky130_stdcells/diode_2.sym} 1730 -840 2 0 {name=x74 VGND=VSS VNB=VSS VPB=VDD VPWR=VDD prefix=sky130_fd_sc_hd__ 
}
C {sky130_stdcells/bufbuf_16.sym} 1930 -790 0 0 {name=x75 VGND=VSS VNB=VSS VPB=VDD VPWR=VDD prefix=sky130_fd_sc_hd__ 
}
C {sky130_stdcells/diode_2.sym} 1900 -750 2 0 {name=x76 VGND=VSS VNB=VSS VPB=VDD VPWR=VDD prefix=sky130_fd_sc_hd__ 
}
C {sky130_stdcells/diode_2.sym} 1730 -750 2 0 {name=x77 VGND=VSS VNB=VSS VPB=VDD VPWR=VDD prefix=sky130_fd_sc_hd__ 
}
C {sky130_stdcells/bufbuf_16.sym} 1930 -700 0 0 {name=x78 VGND=VSS VNB=VSS VPB=VDD VPWR=VDD prefix=sky130_fd_sc_hd__ 
}
C {sky130_stdcells/diode_2.sym} 1900 -660 2 0 {name=x79 VGND=VSS VNB=VSS VPB=VDD VPWR=VDD prefix=sky130_fd_sc_hd__ 
}
C {sky130_stdcells/diode_2.sym} 1730 -660 2 0 {name=x80 VGND=VSS VNB=VSS VPB=VDD VPWR=VDD prefix=sky130_fd_sc_hd__ 
}
C {sky130_stdcells/bufbuf_16.sym} 1930 -610 0 0 {name=x81 VGND=VSS VNB=VSS VPB=VDD VPWR=VDD prefix=sky130_fd_sc_hd__ 
}
C {sky130_stdcells/diode_2.sym} 1900 -570 2 0 {name=x82 VGND=VSS VNB=VSS VPB=VDD VPWR=VDD prefix=sky130_fd_sc_hd__ 
}
C {sky130_stdcells/diode_2.sym} 1730 -570 2 0 {name=x83 VGND=VSS VNB=VSS VPB=VDD VPWR=VDD prefix=sky130_fd_sc_hd__ 
}
C {sky130_stdcells/bufbuf_16.sym} 2700 -970 0 0 {name=x84 VGND=VSS VNB=VSS VPB=VDD VPWR=VDD prefix=sky130_fd_sc_hd__ 
}
C {sky130_stdcells/diode_2.sym} 2670 -930 2 0 {name=x85 VGND=VSS VNB=VSS VPB=VDD VPWR=VDD prefix=sky130_fd_sc_hd__ 
}
C {sky130_stdcells/diode_2.sym} 2500 -930 2 0 {name=x86 VGND=VSS VNB=VSS VPB=VDD VPWR=VDD prefix=sky130_fd_sc_hd__ 
}
C {sky130_stdcells/bufbuf_16.sym} 2700 -880 0 0 {name=x87 VGND=VSS VNB=VSS VPB=VDD VPWR=VDD prefix=sky130_fd_sc_hd__ 
}
C {sky130_stdcells/diode_2.sym} 2670 -840 2 0 {name=x88 VGND=VSS VNB=VSS VPB=VDD VPWR=VDD prefix=sky130_fd_sc_hd__ 
}
C {sky130_stdcells/diode_2.sym} 2500 -840 2 0 {name=x89 VGND=VSS VNB=VSS VPB=VDD VPWR=VDD prefix=sky130_fd_sc_hd__ 
}
C {sky130_stdcells/bufbuf_16.sym} 2700 -790 0 0 {name=x90 VGND=VSS VNB=VSS VPB=VDD VPWR=VDD prefix=sky130_fd_sc_hd__ 
}
C {sky130_stdcells/diode_2.sym} 2670 -750 2 0 {name=x91 VGND=VSS VNB=VSS VPB=VDD VPWR=VDD prefix=sky130_fd_sc_hd__ 
}
C {sky130_stdcells/diode_2.sym} 2500 -750 2 0 {name=x92 VGND=VSS VNB=VSS VPB=VDD VPWR=VDD prefix=sky130_fd_sc_hd__ 
}
C {sky130_stdcells/bufbuf_16.sym} 2700 -700 0 0 {name=x93 VGND=VSS VNB=VSS VPB=VDD VPWR=VDD prefix=sky130_fd_sc_hd__ 
}
C {sky130_stdcells/diode_2.sym} 2670 -660 2 0 {name=x94 VGND=VSS VNB=VSS VPB=VDD VPWR=VDD prefix=sky130_fd_sc_hd__ 
}
C {sky130_stdcells/diode_2.sym} 2500 -660 2 0 {name=x95 VGND=VSS VNB=VSS VPB=VDD VPWR=VDD prefix=sky130_fd_sc_hd__ 
}
C {sky130_stdcells/bufbuf_16.sym} 2700 -610 0 0 {name=x96 VGND=VSS VNB=VSS VPB=VDD VPWR=VDD prefix=sky130_fd_sc_hd__ 
}
C {sky130_stdcells/diode_2.sym} 2670 -570 2 0 {name=x97 VGND=VSS VNB=VSS VPB=VDD VPWR=VDD prefix=sky130_fd_sc_hd__ 
}
C {sky130_stdcells/diode_2.sym} 2500 -570 2 0 {name=x98 VGND=VSS VNB=VSS VPB=VDD VPWR=VDD prefix=sky130_fd_sc_hd__ 
}
C {devices/ipin.sym} 180 -40 0 0 {name=p8 lab=sample_sw_buf_in
}
C {devices/opin.sym} 240 -40 0 0 {name=p1 lab=sample_sw_buf_out
}
C {sky130_stdcells/bufbuf_16.sym} 690 -1100 0 0 {name=x99 VGND=VSS VNB=VSS VPB=VDD VPWR=VDD prefix=sky130_fd_sc_hd__ 
}
C {sky130_stdcells/diode_2.sym} 650 -1060 2 0 {name=x100 VGND=VSS VNB=VSS VPB=VDD VPWR=VDD prefix=sky130_fd_sc_hd__ 
}
C {devices/lab_pin.sym} 400 -1100 0 0 {name=l1 sig_type=std_logic lab=sample_sw_buf_in
}
C {devices/lab_pin.sym} 740 -1100 2 0 {name=l1 sig_type=std_logic lab=sample_sw_buf_out
}
C {devices/code.sym} 1290 -60 0 0 {name=TT_MODELS
only_toplevel=true
format="tcleval( @value )"
value="*.lib $::SKYWATER_MODELS/sky130.lib.spice tt
.include $::SKYWATER_STDCELLS/sky130_fd_sc_hd.spice
"
spice_ignore=false}
